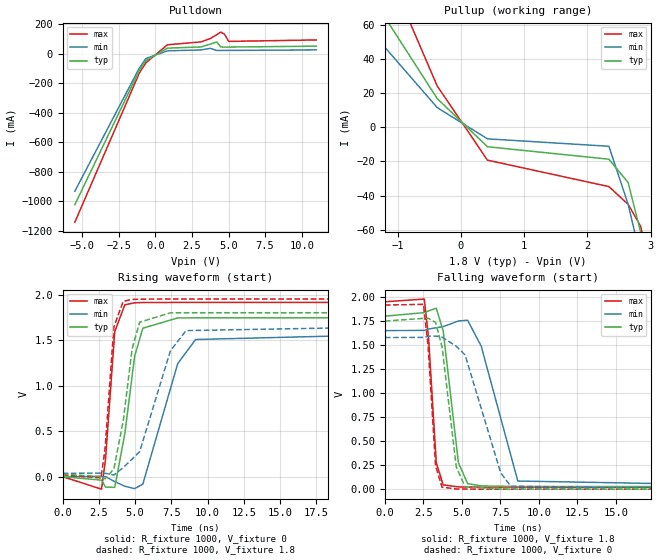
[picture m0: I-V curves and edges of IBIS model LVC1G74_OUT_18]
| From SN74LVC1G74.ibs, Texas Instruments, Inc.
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[Model]   LVC1G74_OUT_18
Model_type  Output
Vref =   0
Rref =   1000
Cref =   30p
Vmeas =   0.9
| variable   typ   min   max
C_comp   9.87pF   6.40pF   15.74pF
| C_pullup   9.16pF   6.40pF   10.35pF
| C_pulldown   10.57pF   6.62pF   15.74pF
[Temperature Range]   40   100   -40
| Ambient temperature   25   85   -40
[Voltage range]   1.8   1.65   1.95
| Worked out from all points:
|   slope of the pulldown table from 0 to 0.27 V, typ, clamps not added: 16.6 ohm
|   slope of the pullup table from 0 to 0.27 V, typ, clamps not added: 33 ohm
|   rising waveform, R_fixture 1000, V_fixture 0: 20-80 % time 864ps typ, 1.55ns min, 502ps max; typ from 0 V to 1.74 V
|   falling waveform, R_fixture 1000, V_fixture 1.8: 20-80 % time 710ps typ, 1.27ns min, 426ps max; typ from 1.8 V to 0.027 V
|   rising waveform, R_fixture 1000, V_fixture 1.8: 20-80 % time 860ps typ, 1.68ns min, 500ps max; typ from 0.027 V to 1.8 V
|   falling waveform, R_fixture 1000, V_fixture 0: 20-80 % time 741ps typ, 1.55ns min, 432ps max; typ from 1.75 V to 0 V
[Pulldown]
| LVC1G74_OUT_18
|   Voltage   I(typ)   I(min)   I(max)
-5.5V     -1.024A    -932.8mA   -1.143A
-1.25V    -145.7mA   -126.9mA   -167.2mA
-1.105V   -116mA     -100.2mA   -133.6mA
-650mV    -46.91mA   -33.3mA    -62.35mA
825mV     37.35mA    19.19mA    60.06mA
3.115V    45.49mA    25.17mA    79.66mA
3.755V    64.52mA    35.93mA    102.7mA
4.19V     79.14mA    21.53mA    128.2mA
4.47V     45.47mA    21.68mA    146.2mA
4.725V    44.49mA    21.83mA    131.7mA
5.01V     44.71mA    22mA       83.05mA
11V       50.72mA    25.33mA    92.94mA
[Pullup]
| LVC1G74_OUT_18
|   Voltage   I(typ)   I(min)   I(max)
-5.5V     449.7mA    254mA      638.5mA
-2.225V   143.3mA    107.6mA    207.3mA
-1.755V   105.1mA    78.04mA    153.5mA
-1.195V   63.95mA    46.44mA    94.81mA
-375mV    16.75mA    11.48mA    24.15mA
420mV     -11.47mA   -6.842mA   -19.31mA
2.34V     -18.76mA   -11.2mA    -34.79mA
2.645V    -32.43mA   -45.25mA   -45.19mA
2.84V     -61.19mA   -75.65mA   -57.82mA
2.99V     -86.8mA    -100.4mA   -81.09mA
3.08V     -102.8mA   -115.6mA   -97.77mA
11V       -1.709A    -1.61A     -1.847A
[Ramp]
| LVC1G74_OUT_18
| variable   typ   min   max
dV/dt_r   1.13/9.33E-10   1.02/1.66E-09   1.24/5.42E-10
dV/dt_f   1.11/7.58E-10   1.04/1.40E-09   1.20/4.51E-10
R_load = 1000
[Rising Waveform]
| LVC1G74_OUT_18
R_fixture =   1000
C_fixture =   0
L_fixture =   0
V_fixture =   0
V_fixture_min = 0
V_fixture_max = 0
|   Time   V(typ)   V(min)   V(max)
0s        112.7pV    7.663nV    3.037nV
2.675ns   -37.7mV    3.112mV    -136.9mV
2.95ns    -114.1mV   788.1uV    188.3mV
3.59ns    -117.2mV   -54.58mV   1.593V
4.285ns   471.1mV    -104.2mV   1.887V
4.965ns   1.324V     -130.9mV   1.909V
5.53ns    1.63V      -81.37mV   1.912V
7.94ns    1.743V     1.242V     1.913V
9.175ns   1.744V     1.506V     1.913V
24.99ns   1.744V     1.569V     1.913V
[Falling Waveform]
| LVC1G74_OUT_18
R_fixture =   1000
C_fixture =   0
L_fixture =   0
V_fixture =   1.8
V_fixture_min = 1.65
V_fixture_max = 1.95
|   Time   V(typ)   V(min)   V(max)
0s        1.8V       1.65V      1.95V
2.555ns   1.837V     1.652V     1.978V
2.835ns   1.855V     1.666V     1.565V
3.33ns    1.883V     1.68V      276.8mV
3.78ns    1.647V     1.691V     44.43mV
4.77ns    275.6mV    1.75V      23.85mV
5.365ns   57.97mV    1.758V     22.04mV
6.245ns   33.95mV    1.49V      21.31mV
8.625ns   27.48mV    84.78mV    21.1mV
24.99ns   26.98mV    37.16mV    21.09mV
[Rising Waveform]
| LVC1G74_OUT_18
R_fixture =   1000
C_fixture =   0
L_fixture =   0
V_fixture =   1.8
V_fixture_min = 1.65
V_fixture_max = 1.95
|   Time   V(typ)   V(min)   V(max)
0s        26.95mV    37.1mV     21.07mV
2.64ns    2.161mV    39.78mV    -13.92mV
2.92ns    -24.03mV   38.22mV    305.2mV
3.53ns    84.62mV    17.9mV     1.647V
4.18ns    618.1mV    101.4mV    1.926V
4.79ns    1.405V     193.6mV    1.946V
5.31ns    1.696V     275.1mV    1.949V
7.435ns   1.799V     1.382V     1.95V
8.515ns   1.8V       1.604V     1.95V
24.99ns   1.8V       1.65V      1.95V
[Falling Waveform]
| LVC1G74_OUT_18
R_fixture =   1000
C_fixture =   0
L_fixture =   0
V_fixture =   0
V_fixture_min = 0
V_fixture_max = 0
|   Time   V(typ)   V(min)   V(max)
0s        1.749V     1.578V     1.916V
2.5ns     1.777V     1.579V     1.923V
2.8ns     1.779V     1.592V     1.493V
3.285ns   1.735V     1.593V     242mV
3.705ns   1.482V     1.582V     20.3mV
4.63ns    232.3mV    1.487V     2.377mV
5.205ns   23.88mV    1.396V     794.4uV
7.515ns   655.6uV    170mV      36.53uV
8.17ns    333.7uV    30.3mV     26.12uV
24.99ns   22.05uV    43.46uV    13.72uV
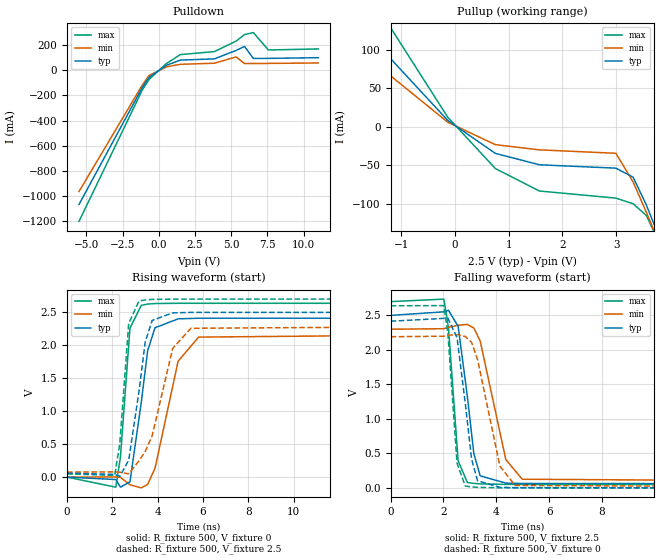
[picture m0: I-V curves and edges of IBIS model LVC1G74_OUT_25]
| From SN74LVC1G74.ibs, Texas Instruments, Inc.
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[Model]   LVC1G74_OUT_25
Model_type  Output
Vref =   0
Rref =   500
Cref =   30p
Vmeas =   1.25
| variable   typ   min   max
C_comp   9.69pF   6.16pF   13.52pF
| C_pullup   9.65pF   6.16pF   11.31pF
| C_pulldown   9.73pF   6.38pF   13.52pF
[Temperature Range]   40   100   -40
| Ambient temperature   25   85   -40
[Voltage range]   2.5   2.3   2.7
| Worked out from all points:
|   slope of the pulldown table from 0 to 0.375 V, typ, clamps not added: 13.1 ohm
|   slope of the pullup table from 0 to 0.375 V, typ, clamps not added: 19 ohm
|   rising waveform, R_fixture 500, V_fixture 0: 20-80 % time 499ps typ, 783ps min, 314ps max; typ from 0 V to 2.41 V
|   falling waveform, R_fixture 500, V_fixture 2.5: 20-80 % time 442ps typ, 694ps min, 283ps max; typ from 2.5 V to 0.06 V
|   rising waveform, R_fixture 500, V_fixture 2.5: 20-80 % time 527ps typ, 930ps min, 320ps max; typ from 0.06 V to 2.5 V
|   falling waveform, R_fixture 500, V_fixture 0: 20-80 % time 430ps typ, 688ps min, 277ps max; typ from 2.42 V to 0 V
[Pulldown]
| LVC1G74_OUT_25
|   Voltage   I(typ)   I(min)   I(max)
-5.5V     -1.065A    -962.2mA   -1.199A
-1.53V    -221.1mA   -193.8mA   -251.2mA
-1.17V    -142.7mA   -123.7mA   -162.8mA
-670mV    -56.67mA   -41.91mA   -73.36mA
520mV     38.43mA    26.46mA    52.49mA
1.485V    80.34mA    46.87mA    124mA
3.84V     90.07mA    55.63mA    147.9mA
5.34V     157.5mA    105.9mA    231.4mA
5.91V     188.7mA    52.63mA    282.8mA
6.525V    93.57mA    53.14mA    298.9mA
7.56V     94.12mA    54.12mA    160.7mA
11V       99.65mA    57.57mA    168.9mA
[Pullup]
| LVC1G74_OUT_25
|   Voltage   I(typ)   I(min)   I(max)
-5.5V     533.4mA    418.6mA    746.4mA
-2.34V    192.7mA    147.4mA    275.6mA
-1.735V   134.9mA    102mA      194.6mA
-1.32V    97.81mA    73.23mA    142.1mA
-135mV    8.418mA    6.055mA    12.49mA
750mV     -34.38mA   -23.05mA   -54.11mA
1.57V     -49.22mA   -29.81mA   -83.34mA
2.995V    -53.63mA   -34.3mA    -92.61mA
3.315V    -65.3mA    -71.46mA   -99.87mA
3.565V    -101.9mA   -111.4mA   -115.4mA
3.75V     -134.3mA   -142.6mA   -143.5mA
11V       -1.614A    -1.516A    -1.761A
[Ramp]
| LVC1G74_OUT_25
| variable   typ   min   max
dV/dt_r   1.55/5.40E-10   1.41/8.44E-10   1.69/3.46E-10
dV/dt_f   1.51/4.62E-10   1.38/7.25E-10   1.64/2.93E-10
R_load = 500
[Rising Waveform]
| LVC1G74_OUT_25
R_fixture =   500
C_fixture =   0
L_fixture =   0
V_fixture =   0
V_fixture_min = 0
V_fixture_max = 0
|   Time   V(typ)   V(min)   V(max)
0s        123.6pV    5.747nV    2.756nV
2.15ns    -36.05mV   2.97mV     -152.1mV
2.355ns   -151.7mV   -3.715mV   306.7mV
2.775ns   -71.24mV   -115.9mV   2.26V
3.275ns   1.138V     -162.5mV   2.606V
3.555ns   1.917V     -108.8mV   2.625V
3.88ns    2.266V     133.7mV    2.633V
4.9ns     2.401V     1.759V     2.637V
5.805ns   2.41V      2.124V     2.637V
24.99ns   2.411V     2.183V     2.637V
[Falling Waveform]
| LVC1G74_OUT_25
R_fixture =   500
C_fixture =   0
L_fixture =   0
V_fixture =   2.5
V_fixture_min = 2.3
V_fixture_max = 2.7
|   Time   V(typ)   V(min)   V(max)
0s        2.5V       2.3V       2.7V
2.015ns   2.552V     2.307V     2.736V
2.19ns    2.574V     2.327V     2.319V
2.555ns   2.341V     2.358V     391.1mV
2.905ns   1.325V     2.369V     77.39mV
3.15ns    496.8mV    2.317V     64.84mV
3.39ns    173.8mV    2.129V     57.89mV
4.36ns    69.34mV    409.9mV    50.25mV
4.98ns    63.19mV    125.4mV    49.62mV
24.99ns   60.11mV    77.11mV    49.35mV
[Rising Waveform]
| LVC1G74_OUT_25
R_fixture =   500
C_fixture =   0
L_fixture =   0
V_fixture =   2.5
V_fixture_min = 2.3
V_fixture_max = 2.7
|   Time   V(typ)   V(min)   V(max)
0s        60.06mV    77.04mV    49.31mV
2.1ns     41.88mV    79.61mV    26.62mV
2.325ns   10.35mV    75.47mV    502.4mV
2.72ns    257.9mV    50.15mV    2.331V
3.175ns   1.304V     248.6mV    2.672V
3.45ns    2.053V     390mV      2.688V
3.755ns   2.377V     628.1mV    2.696V
4.66ns    2.491V     1.953V     2.7V
5.465ns   2.499V     2.258V     2.7V
24.99ns   2.5V       2.3V       2.7V
[Falling Waveform]
| LVC1G74_OUT_25
R_fixture =   500
C_fixture =   0
L_fixture =   0
V_fixture =   0
V_fixture_min = 0
V_fixture_max = 0
|   Time   V(typ)   V(min)   V(max)
0s        2.416V     2.191V     2.64V
2.01ns    2.457V     2.198V     2.642V
2.165ns   2.462V     2.213V     2.249V
2.515ns   2.175V     2.221V     355.4mV
2.825ns   1.228V     2.195V     26.7mV
3.065ns   413.3mV    2.11V      13.03mV
3.29ns    102.7mV    1.863V     7.683mV
4.135ns   7.682mV    315.3mV    1.045mV
4.71ns    2.494mV    35.36mV    353.3uV
24.99ns   40.77uV    56.55uV    33.59uV
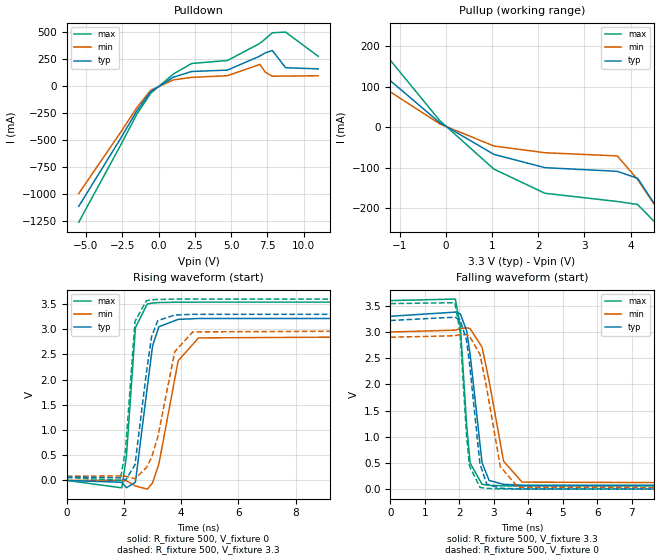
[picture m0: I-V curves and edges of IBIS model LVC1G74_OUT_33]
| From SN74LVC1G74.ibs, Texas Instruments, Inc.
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[Model]   LVC1G74_OUT_33
Model_type  Output
Vref =   0
Rref =   500
Cref =   50p
Vmeas =   1.5
| variable   typ   min   max
C_comp   9.42pF   5.86pF   12.63pF
| C_pullup   9.86pF   5.86pF   11.98pF
| C_pulldown   8.98pF   6.19pF   12.63pF
[Temperature Range]   40   100   -40
| Ambient temperature   25   85   -40
[Voltage range]   3.3   3   3.6
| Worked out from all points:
|   slope of the pulldown table from 0 to 0.495 V, typ, clamps not added: 11.3 ohm
|   slope of the pullup table from 0 to 0.495 V, typ, clamps not added: 13.6 ohm
|   rising waveform, R_fixture 500, V_fixture 0: 20-80 % time 365ps typ, 547ps min, 242ps max; typ from 0 V to 3.22 V
|   falling waveform, R_fixture 500, V_fixture 3.3: 20-80 % time 308ps typ, 467ps min, 211ps max; typ from 3.3 V to 0.069 V
|   rising waveform, R_fixture 500, V_fixture 3.3: 20-80 % time 383ps typ, 609ps min, 251ps max; typ from 0.069 V to 3.3 V
|   falling waveform, R_fixture 500, V_fixture 0: 20-80 % time 297ps typ, 447ps min, 207ps max; typ from 3.22 V to 0 V
[Pulldown]
| LVC1G74_OUT_33
|   Voltage   I(typ)   I(min)   I(max)
-5.5V     -1.112A    -993.8mA   -1.259A
-2.645V   -490.3mA   -433.2mA   -553.8mA
-1.49V    -226.9mA   -197.7mA   -257.3mA
-540mV    -51.04mA   -37.69mA   -65.27mA
1.025V    83.38mA    58mA       112.9mA
2.285V    136mA      81.66mA    210.1mA
4.75V     148.7mA    96.8mA     237.9mA
6.98V     278.7mA    201.6mA    396.3mA
7.35V     308.5mA    129.4mA    437mA
7.84V     330.1mA    92.52mA    494.2mA
8.75V     170.8mA    93.27mA    500.6mA
11V       160mA      96.49mA    276.8mA
[Pullup]
| LVC1G74_OUT_33
|   Voltage   I(typ)   I(min)   I(max)
-5.5V     609.5mA    479.2mA    854.2mA
-3.13V    322.5mA    249.3mA    458mA
-2.385V   237.2mA    181.8mA    339.2mA
-1.845V   177.9mA    135.2mA    255.8mA
-130mV    10.97mA    8.025mA    16.16mA
1.04V     -67.46mA   -46.7mA    -103.9mA
2.145V    -100.4mA   -63.42mA   -163.8mA
3.71V     -109.5mA   -71.26mA   -184.2mA
4.15V     -126.7mA   -129.5mA   -191.6mA
4.765V    -233mA     -235.6mA   -263.4mA
4.95V     -268.4mA   -268.9mA   -301.3mA
11V       -1.523A    -1.428A    -1.684A
[Ramp]
| LVC1G74_OUT_33
| variable   typ   min   max
dV/dt_r   2.05/3.93E-10   1.85/5.91E-10   2.24/2.67E-10
dV/dt_f   1.99/3.24E-10   1.80/4.85E-10   2.18/2.25E-10
R_load = 500
[Rising Waveform]
| LVC1G74_OUT_33
R_fixture =   500
C_fixture =   0
L_fixture =   0
V_fixture =   0
V_fixture_min = 0
V_fixture_max = 0
|   Time   V(typ)   V(min)   V(max)
0s        141.7pV    4.978nV    2.659nV
1.925ns   -36.7mV    2.946mV    -146.9mV
2.085ns   -146.3mV   -7.647mV   476.3mV
2.4ns     -34.97mV   -109.4mV   3.033V
2.815ns   1.848V     -173.4mV   3.502V
3ns       2.671V     -48.65mV   3.521V
3.22ns    3.05V      326.5mV    3.531V
3.895ns   3.197V     2.375V     3.538V
4.605ns   3.214V     2.829V     3.539V
24.99ns   3.216V     2.894V     3.539V
[Falling Waveform]
| LVC1G74_OUT_33
R_fixture =   500
C_fixture =   0
L_fixture =   0
V_fixture =   3.3
V_fixture_min = 3
V_fixture_max = 3.6
|   Time   V(typ)   V(min)   V(max)
0s        3.3V       3V         3.6V
1.885ns   3.38V      3.036V     3.629V
2.03ns    3.347V     3.065V     3.114V
2.215ns   3.019V     3.082V     1.208V
2.315ns   2.568V     3.064V     497.9mV
2.66ns    504.4mV    2.711V     92.23mV
2.865ns   166.3mV    2.065V     74.67mV
3.285ns   91.77mV    533.3mV    63.5mV
3.82ns    75.94mV    134.7mV    60.12mV
24.99ns   69.39mV    85.93mV    58.96mV
[Rising Waveform]
| LVC1G74_OUT_33
R_fixture =   500
C_fixture =   0
L_fixture =   0
V_fixture =   3.3
V_fixture_min = 3
V_fixture_max = 3.6
|   Time   V(typ)   V(min)   V(max)
0s        69.35mV    85.87mV    58.92mV
1.87ns    51.08mV    88.72mV    1.681mV
2.055ns   5.02mV     82.05mV    606.6mV
2.385ns   311.8mV    34.11mV    3.156V
2.785ns   2.143V     255mV      3.567V
2.965ns   2.854V     454.5mV    3.584V
3.18ns    3.173V     855.8mV    3.593V
3.775ns   3.283V     2.556V     3.599V
4.405ns   3.297V     2.948V     3.6V
24.99ns   3.3V       3V         3.6V
[Falling Waveform]
| LVC1G74_OUT_33
R_fixture =   500
C_fixture =   0
L_fixture =   0
V_fixture =   0
V_fixture_min = 0
V_fixture_max = 0
|   Time   V(typ)   V(min)   V(max)
0s        3.22V      2.9V       3.542V
1.87ns    3.283V     2.929V     3.56V
2.02ns    3.238V     2.951V     3.02V
2.21ns    2.844V     2.95V      1.028V
2.295ns   2.405V     2.925V     444.3mV
2.6ns     480.5mV    2.572V     32.93mV
2.795ns   97.83mV    1.927V     15.54mV
3.19ns    18.26mV    429.8mV    4.689mV
3.7ns     5.601mV    37.12mV    1.293mV
24.99ns   34.32uV    45.15uV    33.32uV
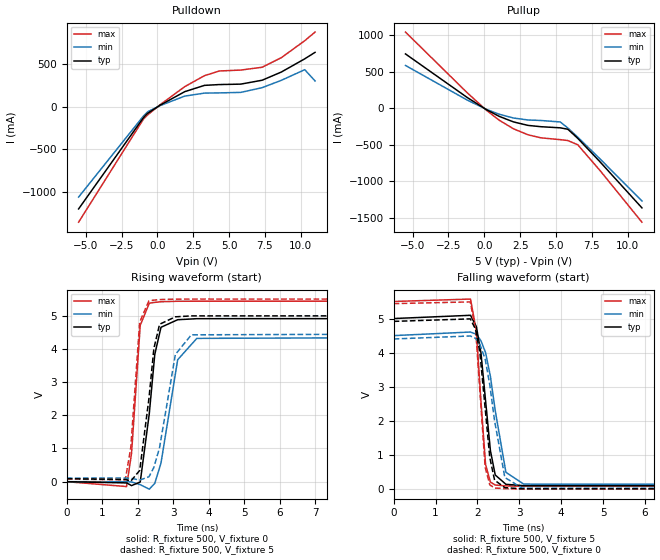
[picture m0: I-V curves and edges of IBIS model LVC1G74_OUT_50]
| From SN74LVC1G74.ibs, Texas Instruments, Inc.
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[Model]   LVC1G74_OUT_50
Model_type  Output
Vref =   0
Rref =   500
Cref =   50p
Vmeas =   2.5
| variable   typ   min   max
C_comp   8.85pF   5.46pF   12.42pF
| C_pullup   9.71pF   5.46pF   12.42pF
| C_pulldown   7.99pF   5.94pF   10.90pF
[Temperature Range]   40   100   -40
| Ambient temperature   25   85   -40
[Voltage range]   5   4.5   5.5
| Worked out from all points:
|   slope of the pulldown table from 0 to 0.75 V, typ, clamps not added: 9.58 ohm
|   slope of the pullup table from 0 to 0.75 V, typ, clamps not added: 9.16 ohm
|   rising waveform, R_fixture 500, V_fixture 0: 20-80 % time 264ps typ, 375ps min, 192ps max; typ from 0 V to 4.91 V
|   falling waveform, R_fixture 500, V_fixture 5: 20-80 % time 234ps typ, 310ps min, 167ps max; typ from 5 V to 0.09 V
|   rising waveform, R_fixture 500, V_fixture 5: 20-80 % time 277ps typ, 404ps min, 200ps max; typ from 0.09 V to 5 V
|   falling waveform, R_fixture 500, V_fixture 0: 20-80 % time 224ps typ, 303ps min, 167ps max; typ from 4.92 V to 0 V
[Pulldown]
| LVC1G74_OUT_50
|   Voltage   I(typ)   I(min)   I(max)
-5.5V     -1.198A    -1.059A    -1.354A
-970mV    -125.1mA   -106.1mA   -141.7mA
-675mV    -74.35mA   -56.48mA   -92.74mA
205mV     22.29mA    16.59mA    27.99mA
1.905V    179.2mA    127mA      238mA
3.285V    253.2mA    162.4mA    367.3mA
4.325V    262.7mA    164.8mA    422.2mA
5.815V    267.8mA    170.7mA    433mA
7.31V     313.8mA    226.4mA    466mA
8.65V     410.1mA    312.7mA    578.8mA
10.28V    565mA      437.4mA    777.7mA
11V       641.2mA    305.2mA    879.1mA
[Pullup]
| LVC1G74_OUT_50
|   Voltage   I(typ)   I(min)   I(max)
-5.5V     745.2mA    587.5mA    1.044A
-1.18V    147.6mA    112.6mA    211.7mA
170mV     -19.98mA   -14.91mA   -29.14mA
1.04V     -109.2mA   -79.97mA   -161.6mA
2.045V    -185.4mA   -131.8mA   -280mA
3.05V     -232.7mA   -158.7mA   -361.3mA
3.945V    -250.5mA   -165.3mA   -402.5mA
5.3V      -265.9mA   -185.4mA   -427.7mA
5.83V     -285.1mA   -268.2mA   -440mA
6.525V    -410.2mA   -394.3mA   -498.1mA
8.085V    -732.8mA   -692.6mA   -852.4mA
11V       -1.361A    -1.267A    -1.557A
[Ramp]
| LVC1G74_OUT_50
| variable   typ   min   max
dV/dt_r   3.08/2.84E-10   2.78/4.08E-10   3.39/2.04E-10
dV/dt_f   3.01/2.51E-10   2.70/3.25E-10   3.32/1.78E-10
R_load = 500
[Rising Waveform]
| LVC1G74_OUT_50
R_fixture =   500
C_fixture =   0
L_fixture =   0
V_fixture =   0
V_fixture_min = 0
V_fixture_max = 0
|   Time   V(typ)   V(min)   V(max)
0s        181.8pV    4.248nV    2.638nV
1.685ns   -36.92mV   1.036mV    -147mV
1.825ns   -118.2mV   -9.155mV   853.5mV
2.07ns    -10.87mV   -89.59mV   4.709V
2.325ns   2.047V     -225.5mV   5.375V
2.48ns    3.833V     -50.53mV   5.4V
2.655ns   4.65V      559.4mV    5.419V
3.125ns   4.878V     3.672V     5.434V
3.665ns   4.909V     4.316V     5.435V
24.99ns   4.914V     4.397V     5.435V
[Falling Waveform]
| LVC1G74_OUT_50
R_fixture =   500
C_fixture =   0
L_fixture =   0
V_fixture =   5
V_fixture_min = 4.5
V_fixture_max = 5.5
|   Time   V(typ)   V(min)   V(max)
0s        5V         4.5V       5.5V
1.835ns   5.095V     4.605V     5.571V
1.975ns   4.764V     4.538V     4.627V
2.085ns   3.991V     4.348V     2.562V
2.195ns   2.585V     4.001V     721.3mV
2.31ns    1.131V     3.306V     209.2mV
2.425ns   416.5mV    2.304V     120.8mV
2.68ns    142.7mV    493.8mV    95.94mV
3.105ns   102.5mV    148.9mV    82.81mV
24.99ns   89.64mV    107.6mV    78.98mV
[Rising Waveform]
| LVC1G74_OUT_50
R_fixture =   500
C_fixture =   0
L_fixture =   0
V_fixture =   5
V_fixture_min = 4.5
V_fixture_max = 5.5
|   Time   V(typ)   V(min)   V(max)
0s        89.62mV    107.6mV    78.96mV
1.65ns    66.86mV    109mV      57.12mV
1.805ns   18.03mV    101.7mV    1.039V
2.055ns   339.3mV    49.62mV    4.806V
2.315ns   2.502V     146.1mV    5.447V
2.455ns   4.013V     429.8mV    5.467V
2.615ns   4.741V     1.026V     5.484V
3.06ns    4.965V     3.83V      5.498V
3.51ns    4.993V     4.423V     5.5V
24.99ns   5V         4.5V       5.5V
[Falling Waveform]
| LVC1G74_OUT_50
R_fixture =   500
C_fixture =   0
L_fixture =   0
V_fixture =   0
V_fixture_min = 0
V_fixture_max = 0
|   Time   V(typ)   V(min)   V(max)
0s        4.917V     4.401V     5.437V
1.83ns    4.99V      4.489V     5.488V
1.96ns    4.674V     4.418V     4.64V
2.06ns    3.992V     4.24V      2.861V
2.185ns   2.368V     3.812V     640.5mV
2.295ns   927.7mV    3.06V      127.3mV
2.41ns    263.8mV    2.004V     32.59mV
2.655ns   44.86mV    340.6mV    15.25mV
3.07ns    10.65mV    30.68mV    3.675mV
24.99ns   19.28uV    20.55uV    17.98uV
